VERSION 5.7 ;
  NOWIREEXTENSIONATPIN ON ;
  DIVIDERCHAR "/" ;
  BUSBITCHARS "[]" ;
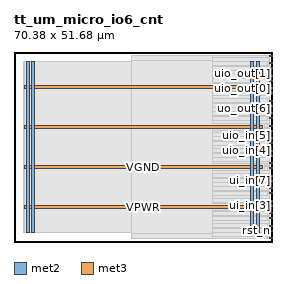
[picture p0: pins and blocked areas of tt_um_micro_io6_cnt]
MACRO tt_um_micro_io6_cnt
  CLASS BLOCK ;
  FOREIGN tt_um_micro_io6_cnt ;
  ORIGIN 0.000 0.000 ;
  SIZE 70.380 BY 51.680 ;
  PIN VGND
    DIRECTION INOUT ;
    USE GROUND ;
    PORT
      LAYER met2 ;
        RECT 4.660 2.480 5.460 49.200 ;
    END
    PORT
      LAYER met2 ;
        RECT 65.840 2.480 66.640 49.200 ;
    END
    PORT
      LAYER met3 ;
        RECT 2.760 19.900 67.620 20.900 ;
    END
    PORT
      LAYER met3 ;
        RECT 2.760 41.660 67.620 42.660 ;
    END
  END VGND
  PIN VPWR
    DIRECTION INOUT ;
    USE POWER ;
    PORT
      LAYER met2 ;
        RECT 3.280 2.480 4.080 49.200 ;
    END
    PORT
      LAYER met2 ;
        RECT 64.460 2.480 65.260 49.200 ;
    END
    PORT
      LAYER met3 ;
        RECT 2.760 9.020 67.620 10.020 ;
    END
    PORT
      LAYER met3 ;
        RECT 2.760 30.780 67.620 31.780 ;
    END
  END VPWR
  PIN clk
    DIRECTION INPUT ;
    USE SIGNAL ;
    ANTENNAGATEAREA 0.852000 ;
    PORT
      LAYER met3 ;
        RECT 69.380 0.870 70.380 1.170 ;
    END
  END clk
  PIN rst_n
    DIRECTION INPUT ;
    USE SIGNAL ;
    ANTENNAGATEAREA 0.213000 ;
    PORT
      LAYER met3 ;
        RECT 69.380 2.910 70.380 3.210 ;
    END
  END rst_n
  PIN ui_in[0]
    DIRECTION INPUT ;
    USE SIGNAL ;
    PORT
      LAYER met3 ;
        RECT 69.380 4.270 70.380 4.570 ;
    END
  END ui_in[0]
  PIN ui_in[1]
    DIRECTION INPUT ;
    USE SIGNAL ;
    PORT
      LAYER met3 ;
        RECT 69.380 6.310 70.380 6.610 ;
    END
  END ui_in[1]
  PIN ui_in[2]
    DIRECTION INPUT ;
    USE SIGNAL ;
    ANTENNAGATEAREA 0.213000 ;
    PORT
      LAYER met3 ;
        RECT 69.380 7.670 70.380 7.970 ;
    END
  END ui_in[2]
  PIN ui_in[3]
    DIRECTION INPUT ;
    USE SIGNAL ;
    ANTENNAGATEAREA 0.213000 ;
    PORT
      LAYER met3 ;
        RECT 69.380 9.710 70.380 10.010 ;
    END
  END ui_in[3]
  PIN ui_in[4]
    DIRECTION INPUT ;
    USE SIGNAL ;
    ANTENNAGATEAREA 0.213000 ;
    PORT
      LAYER met3 ;
        RECT 69.380 11.070 70.380 11.370 ;
    END
  END ui_in[4]
  PIN ui_in[5]
    DIRECTION INPUT ;
    USE SIGNAL ;
    ANTENNAGATEAREA 0.213000 ;
    PORT
      LAYER met3 ;
        RECT 69.380 13.110 70.380 13.410 ;
    END
  END ui_in[5]
  PIN ui_in[6]
    DIRECTION INPUT ;
    USE SIGNAL ;
    ANTENNAGATEAREA 0.213000 ;
    PORT
      LAYER met3 ;
        RECT 69.380 14.470 70.380 14.770 ;
    END
  END ui_in[6]
  PIN ui_in[7]
    DIRECTION INPUT ;
    USE SIGNAL ;
    ANTENNAGATEAREA 0.213000 ;
    PORT
      LAYER met3 ;
        RECT 69.380 16.510 70.380 16.810 ;
    END
  END ui_in[7]
  PIN uio_in[0]
    DIRECTION INPUT ;
    USE SIGNAL ;
    ANTENNAGATEAREA 0.213000 ;
    PORT
      LAYER met3 ;
        RECT 69.380 17.870 70.380 18.170 ;
    END
  END uio_in[0]
  PIN uio_in[1]
    DIRECTION INPUT ;
    USE SIGNAL ;
    ANTENNAGATEAREA 0.213000 ;
    PORT
      LAYER met3 ;
        RECT 69.380 19.910 70.380 20.210 ;
    END
  END uio_in[1]
  PIN uio_in[2]
    DIRECTION INPUT ;
    USE SIGNAL ;
    ANTENNAGATEAREA 0.213000 ;
    PORT
      LAYER met3 ;
        RECT 69.380 21.270 70.380 21.570 ;
    END
  END uio_in[2]
  PIN uio_in[3]
    DIRECTION INPUT ;
    USE SIGNAL ;
    ANTENNAGATEAREA 0.213000 ;
    PORT
      LAYER met3 ;
        RECT 69.380 23.310 70.380 23.610 ;
    END
  END uio_in[3]
  PIN uio_in[4]
    DIRECTION INPUT ;
    USE SIGNAL ;
    ANTENNAGATEAREA 0.213000 ;
    PORT
      LAYER met3 ;
        RECT 69.380 24.670 70.380 24.970 ;
    END
  END uio_in[4]
  PIN uio_in[5]
    DIRECTION INPUT ;
    USE SIGNAL ;
    ANTENNAGATEAREA 0.213000 ;
    PORT
      LAYER met3 ;
        RECT 69.380 26.710 70.380 27.010 ;
    END
  END uio_in[5]
  PIN uio_out[0]
    DIRECTION OUTPUT ;
    USE SIGNAL ;
    ANTENNADIFFAREA 0.429000 ;
    PORT
      LAYER met3 ;
        RECT 69.380 41.670 70.380 41.970 ;
    END
  END uio_out[0]
  PIN uio_out[1]
    DIRECTION OUTPUT ;
    USE SIGNAL ;
    ANTENNADIFFAREA 0.429000 ;
    PORT
      LAYER met3 ;
        RECT 69.380 43.710 70.380 44.010 ;
    END
  END uio_out[1]
  PIN uio_out[2]
    DIRECTION OUTPUT ;
    USE SIGNAL ;
    ANTENNADIFFAREA 0.429000 ;
    PORT
      LAYER met3 ;
        RECT 69.380 45.070 70.380 45.370 ;
    END
  END uio_out[2]
  PIN uio_out[3]
    DIRECTION OUTPUT ;
    USE SIGNAL ;
    ANTENNADIFFAREA 0.429000 ;
    PORT
      LAYER met3 ;
        RECT 69.380 47.110 70.380 47.410 ;
    END
  END uio_out[3]
  PIN uio_out[4]
    DIRECTION OUTPUT ;
    USE SIGNAL ;
    ANTENNADIFFAREA 0.429000 ;
    PORT
      LAYER met3 ;
        RECT 69.380 48.470 70.380 48.770 ;
    END
  END uio_out[4]
  PIN uio_out[5]
    DIRECTION OUTPUT ;
    USE SIGNAL ;
    ANTENNADIFFAREA 0.429000 ;
    PORT
      LAYER met3 ;
        RECT 69.380 50.510 70.380 50.810 ;
    END
  END uio_out[5]
  PIN uo_out[0]
    DIRECTION OUTPUT ;
    USE SIGNAL ;
    ANTENNADIFFAREA 0.429000 ;
    PORT
      LAYER met3 ;
        RECT 69.380 28.070 70.380 28.370 ;
    END
  END uo_out[0]
  PIN uo_out[1]
    DIRECTION OUTPUT ;
    USE SIGNAL ;
    ANTENNADIFFAREA 0.429000 ;
    PORT
      LAYER met3 ;
        RECT 69.380 30.110 70.380 30.410 ;
    END
  END uo_out[1]
  PIN uo_out[2]
    DIRECTION OUTPUT ;
    USE SIGNAL ;
    ANTENNADIFFAREA 0.429000 ;
    PORT
      LAYER met3 ;
        RECT 69.380 31.470 70.380 31.770 ;
    END
  END uo_out[2]
  PIN uo_out[3]
    DIRECTION OUTPUT ;
    USE SIGNAL ;
    ANTENNADIFFAREA 0.429000 ;
    PORT
      LAYER met3 ;
        RECT 69.380 33.510 70.380 33.810 ;
    END
  END uo_out[3]
  PIN uo_out[4]
    DIRECTION OUTPUT ;
    USE SIGNAL ;
    ANTENNADIFFAREA 0.429000 ;
    PORT
      LAYER met3 ;
        RECT 69.380 34.870 70.380 35.170 ;
    END
  END uo_out[4]
  PIN uo_out[5]
    DIRECTION OUTPUT ;
    USE SIGNAL ;
    ANTENNADIFFAREA 0.429000 ;
    PORT
      LAYER met3 ;
        RECT 69.380 36.910 70.380 37.210 ;
    END
  END uo_out[5]
  PIN uo_out[6]
    DIRECTION OUTPUT ;
    USE SIGNAL ;
    ANTENNADIFFAREA 0.429000 ;
    PORT
      LAYER met3 ;
        RECT 69.380 38.270 70.380 38.570 ;
    END
  END uo_out[6]
  PIN uo_out[7]
    DIRECTION OUTPUT ;
    USE SIGNAL ;
    ANTENNADIFFAREA 0.429000 ;
    PORT
      LAYER met3 ;
        RECT 69.380 40.310 70.380 40.610 ;
    END
  END uo_out[7]
  OBS
      LAYER nwell ;
        RECT 2.570 2.635 67.810 49.150 ;
      LAYER li1 ;
        RECT 2.760 2.635 67.620 49.045 ;
      LAYER met1 ;
        RECT 2.760 2.480 69.390 49.200 ;
      LAYER met2 ;
        RECT 31.840 49.480 69.370 50.845 ;
        RECT 31.840 2.200 64.180 49.480 ;
        RECT 65.540 2.200 65.560 49.480 ;
        RECT 66.920 2.200 69.370 49.480 ;
        RECT 31.840 0.835 69.370 2.200 ;
      LAYER met3 ;
        RECT 53.885 50.110 68.980 50.825 ;
        RECT 53.885 49.170 69.395 50.110 ;
        RECT 53.885 48.070 68.980 49.170 ;
        RECT 53.885 47.810 69.395 48.070 ;
        RECT 53.885 46.710 68.980 47.810 ;
        RECT 53.885 45.770 69.395 46.710 ;
        RECT 53.885 44.670 68.980 45.770 ;
        RECT 53.885 44.410 69.395 44.670 ;
        RECT 53.885 43.310 68.980 44.410 ;
        RECT 53.885 43.060 69.395 43.310 ;
        RECT 68.020 42.370 69.395 43.060 ;
        RECT 68.020 41.270 68.980 42.370 ;
        RECT 68.020 41.260 69.395 41.270 ;
        RECT 53.885 41.010 69.395 41.260 ;
        RECT 53.885 39.910 68.980 41.010 ;
        RECT 53.885 38.970 69.395 39.910 ;
        RECT 53.885 37.870 68.980 38.970 ;
        RECT 53.885 37.610 69.395 37.870 ;
        RECT 53.885 36.510 68.980 37.610 ;
        RECT 53.885 35.570 69.395 36.510 ;
        RECT 53.885 34.470 68.980 35.570 ;
        RECT 53.885 34.210 69.395 34.470 ;
        RECT 53.885 33.110 68.980 34.210 ;
        RECT 53.885 32.180 69.395 33.110 ;
        RECT 68.020 32.170 69.395 32.180 ;
        RECT 68.020 31.070 68.980 32.170 ;
        RECT 68.020 30.810 69.395 31.070 ;
        RECT 68.020 30.380 68.980 30.810 ;
        RECT 53.885 29.710 68.980 30.380 ;
        RECT 53.885 28.770 69.395 29.710 ;
        RECT 53.885 27.670 68.980 28.770 ;
        RECT 53.885 27.410 69.395 27.670 ;
        RECT 53.885 26.310 68.980 27.410 ;
        RECT 53.885 25.370 69.395 26.310 ;
        RECT 53.885 24.270 68.980 25.370 ;
        RECT 53.885 24.010 69.395 24.270 ;
        RECT 53.885 22.910 68.980 24.010 ;
        RECT 53.885 21.970 69.395 22.910 ;
        RECT 53.885 21.300 68.980 21.970 ;
        RECT 68.020 20.870 68.980 21.300 ;
        RECT 68.020 20.610 69.395 20.870 ;
        RECT 68.020 19.510 68.980 20.610 ;
        RECT 68.020 19.500 69.395 19.510 ;
        RECT 53.885 18.570 69.395 19.500 ;
        RECT 53.885 17.470 68.980 18.570 ;
        RECT 53.885 17.210 69.395 17.470 ;
        RECT 53.885 16.110 68.980 17.210 ;
        RECT 53.885 15.170 69.395 16.110 ;
        RECT 53.885 14.070 68.980 15.170 ;
        RECT 53.885 13.810 69.395 14.070 ;
        RECT 53.885 12.710 68.980 13.810 ;
        RECT 53.885 11.770 69.395 12.710 ;
        RECT 53.885 10.670 68.980 11.770 ;
        RECT 53.885 10.420 69.395 10.670 ;
        RECT 68.020 10.410 69.395 10.420 ;
        RECT 68.020 9.310 68.980 10.410 ;
        RECT 68.020 8.620 69.395 9.310 ;
        RECT 53.885 8.370 69.395 8.620 ;
        RECT 53.885 7.270 68.980 8.370 ;
        RECT 53.885 7.010 69.395 7.270 ;
        RECT 53.885 5.910 68.980 7.010 ;
        RECT 53.885 4.970 69.395 5.910 ;
        RECT 53.885 3.870 68.980 4.970 ;
        RECT 53.885 3.610 69.395 3.870 ;
        RECT 53.885 2.510 68.980 3.610 ;
        RECT 53.885 1.570 69.395 2.510 ;
        RECT 53.885 0.855 68.980 1.570 ;
  END
END tt_um_micro_io6_cnt
END LIBRARY

